One B-rep face of a CAD part: STEP entity #519.
In plain terms, the cylindrical face has radius 15.5 mm (diameter 31 mm), a partial arc.
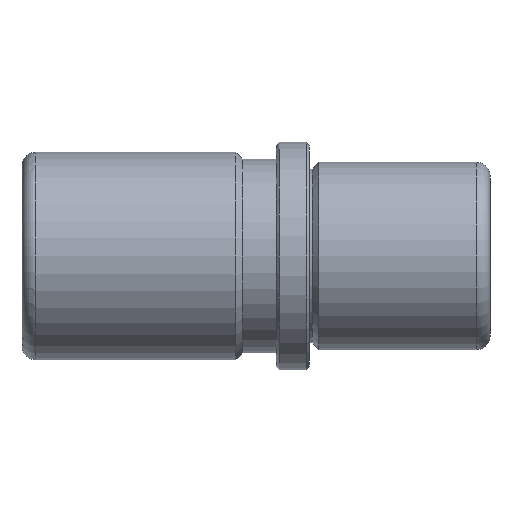
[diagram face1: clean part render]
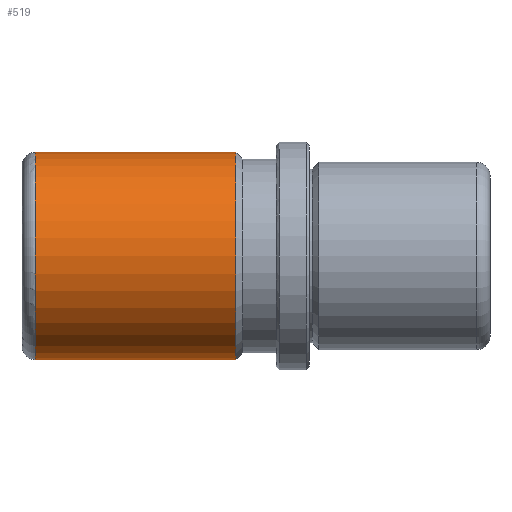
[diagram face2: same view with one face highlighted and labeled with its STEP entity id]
Its self-contained STEP definition (entity closure, numbers rounded to 3 decimals):
#308=CARTESIAN_POINT('Line Origine',(27.,0.,15.5)) ;
#312=CARTESIAN_POINT('Vertex',(-11.,0.,15.5)) ;
#314=CARTESIAN_POINT('Vertex',(-41.,0.,15.5)) ;
#328=CARTESIAN_POINT('Vertex',(-11.,0.,-15.5)) ;
#331=CARTESIAN_POINT('Line Origine',(27.,0.,-15.5)) ;
#335=CARTESIAN_POINT('Vertex',(-41.,0.,-15.5)) ;
#482=CARTESIAN_POINT('Axis2P3D Location',(27.,0.,0.)) ;
#487=CARTESIAN_POINT('Axis2P3D Location',(-11.,0.,0.)) ;
#491=CARTESIAN_POINT('Vertex',(-11.,-15.5,0.)) ;
#494=CARTESIAN_POINT('Axis2P3D Location',(-11.,0.,0.)) ;
#499=CARTESIAN_POINT('Axis2P3D Location',(-41.,0.,0.)) ;
#503=CARTESIAN_POINT('Vertex',(-41.,-15.5,0.)) ;
#506=CARTESIAN_POINT('Axis2P3D Location',(-41.,0.,0.)) ;
#309=DIRECTION('Vector Direction',(-1.,0.,0.)) ;
#332=DIRECTION('Vector Direction',(-1.,0.,0.)) ;
#483=DIRECTION('Axis2P3D Direction',(-1.,-0.,-0.)) ;
#484=DIRECTION('Axis2P3D XDirection',(0.,0.,-1.)) ;
#488=DIRECTION('Axis2P3D Direction',(-1.,-0.,-0.)) ;
#495=DIRECTION('Axis2P3D Direction',(-1.,-0.,-0.)) ;
#500=DIRECTION('Axis2P3D Direction',(-1.,-0.,-0.)) ;
#507=DIRECTION('Axis2P3D Direction',(-1.,-0.,-0.)) ;
#485=AXIS2_PLACEMENT_3D('Cylinder Axis2P3D',#482,#483,#484) ;
#489=AXIS2_PLACEMENT_3D('Circle Axis2P3D',#487,#488,$) ;
#496=AXIS2_PLACEMENT_3D('Circle Axis2P3D',#494,#495,$) ;
#501=AXIS2_PLACEMENT_3D('Circle Axis2P3D',#499,#500,$) ;
#508=AXIS2_PLACEMENT_3D('Circle Axis2P3D',#506,#507,$) ;
#512=ORIENTED_EDGE('',*,*,#337,.T.) ;
#513=ORIENTED_EDGE('',*,*,#493,.F.) ;
#514=ORIENTED_EDGE('',*,*,#498,.F.) ;
#515=ORIENTED_EDGE('',*,*,#316,.T.) ;
#516=ORIENTED_EDGE('',*,*,#505,.T.) ;
#517=ORIENTED_EDGE('',*,*,#510,.T.) ;
#310=VECTOR('Line Direction',#309,1.) ;
#333=VECTOR('Line Direction',#332,1.) ;
#519=ADVANCED_FACE('FAMO-SF1-D18 x 70',(#518),#486,.T.) ;
#490=CIRCLE('generated circle',#489,15.5) ;
#497=CIRCLE('generated circle',#496,15.5) ;
#502=CIRCLE('generated circle',#501,15.5) ;
#509=CIRCLE('generated circle',#508,15.5) ;
#486=CYLINDRICAL_SURFACE('generated cylinder',#485,15.5) ;
#316=EDGE_CURVE('',#313,#315,#311,.T.) ;
#337=EDGE_CURVE('',#336,#329,#334,.F.) ;
#493=EDGE_CURVE('',#492,#329,#490,.F.) ;
#498=EDGE_CURVE('',#313,#492,#497,.F.) ;
#505=EDGE_CURVE('',#315,#504,#502,.F.) ;
#510=EDGE_CURVE('',#504,#336,#509,.F.) ;
#511=EDGE_LOOP('',(#512,#513,#514,#515,#516,#517)) ;
#518=FACE_OUTER_BOUND('',#511,.T.) ;
#311=LINE('Line',#308,#310) ;
#334=LINE('Line',#331,#333) ;
#313=VERTEX_POINT('',#312) ;
#315=VERTEX_POINT('',#314) ;
#329=VERTEX_POINT('',#328) ;
#336=VERTEX_POINT('',#335) ;
#492=VERTEX_POINT('',#491) ;
#504=VERTEX_POINT('',#503) ;
